VERSION 5.7 ;
  NOWIREEXTENSIONATPIN ON ;
  DIVIDERCHAR "/" ;
  BUSBITCHARS "[]" ;
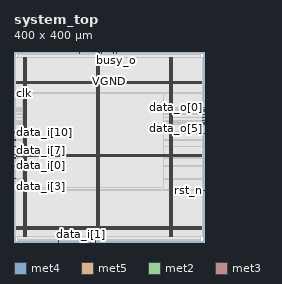
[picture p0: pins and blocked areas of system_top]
MACRO system_top
  CLASS BLOCK ;
  FOREIGN system_top ;
  ORIGIN 0.000 0.000 ;
  SIZE 400.000 BY 400.000 ;
  PIN VGND
    DIRECTION INOUT ;
    USE GROUND ;
    PORT
      LAYER met4 ;
        RECT 24.340 10.640 25.940 389.200 ;
    END
    PORT
      LAYER met4 ;
        RECT 177.940 10.640 179.540 389.200 ;
    END
    PORT
      LAYER met4 ;
        RECT 331.540 10.640 333.140 389.200 ;
    END
    PORT
      LAYER met5 ;
        RECT 5.280 30.030 394.460 31.630 ;
    END
    PORT
      LAYER met5 ;
        RECT 5.280 183.210 394.460 184.810 ;
    END
    PORT
      LAYER met5 ;
        RECT 5.280 336.390 394.460 337.990 ;
    END
  END VGND
  PIN VPWR
    DIRECTION INOUT ;
    USE POWER ;
    PORT
      LAYER met4 ;
        RECT 21.040 10.640 22.640 389.200 ;
    END
    PORT
      LAYER met4 ;
        RECT 174.640 10.640 176.240 389.200 ;
    END
    PORT
      LAYER met4 ;
        RECT 328.240 10.640 329.840 389.200 ;
    END
    PORT
      LAYER met5 ;
        RECT 5.280 26.730 394.460 28.330 ;
    END
    PORT
      LAYER met5 ;
        RECT 5.280 179.910 394.460 181.510 ;
    END
    PORT
      LAYER met5 ;
        RECT 5.280 333.090 394.460 334.690 ;
    END
  END VPWR
  PIN busy_o
    DIRECTION OUTPUT ;
    USE SIGNAL ;
    ANTENNADIFFAREA 0.340600 ;
    PORT
      LAYER met2 ;
        RECT 215.830 396.000 216.110 400.000 ;
    END
  END busy_o
  PIN clk
    DIRECTION INPUT ;
    USE SIGNAL ;
    ANTENNAGATEAREA 0.852000 ;
    ANTENNADIFFAREA 0.434700 ;
    PORT
      LAYER met3 ;
        RECT 0.000 312.840 4.000 313.440 ;
    END
  END clk
  PIN data_i[0]
    DIRECTION INPUT ;
    USE SIGNAL ;
    ANTENNAGATEAREA 0.213000 ;
    ANTENNADIFFAREA 0.434700 ;
    PORT
      LAYER met3 ;
        RECT 0.000 159.840 4.000 160.440 ;
    END
  END data_i[0]
  PIN data_i[10]
    DIRECTION INPUT ;
    USE SIGNAL ;
    ANTENNAGATEAREA 0.159000 ;
    ANTENNADIFFAREA 0.434700 ;
    PORT
      LAYER met3 ;
        RECT 0.000 231.240 4.000 231.840 ;
    END
  END data_i[10]
  PIN data_i[11]
    DIRECTION INPUT ;
    USE SIGNAL ;
    ANTENNAGATEAREA 0.159000 ;
    ANTENNADIFFAREA 0.434700 ;
    PORT
      LAYER met2 ;
        RECT 183.630 396.000 183.910 400.000 ;
    END
  END data_i[11]
  PIN data_i[12]
    DIRECTION INPUT ;
    USE SIGNAL ;
    ANTENNAGATEAREA 0.159000 ;
    ANTENNADIFFAREA 0.434700 ;
    PORT
      LAYER met3 ;
        RECT 0.000 227.840 4.000 228.440 ;
    END
  END data_i[12]
  PIN data_i[13]
    DIRECTION INPUT ;
    USE SIGNAL ;
    ANTENNAGATEAREA 0.159000 ;
    ANTENNADIFFAREA 0.434700 ;
    PORT
      LAYER met2 ;
        RECT 180.410 396.000 180.690 400.000 ;
    END
  END data_i[13]
  PIN data_i[14]
    DIRECTION INPUT ;
    USE SIGNAL ;
    ANTENNAGATEAREA 0.159000 ;
    ANTENNADIFFAREA 0.434700 ;
    PORT
      LAYER met2 ;
        RECT 177.190 396.000 177.470 400.000 ;
    END
  END data_i[14]
  PIN data_i[15]
    DIRECTION INPUT ;
    USE SIGNAL ;
    ANTENNAGATEAREA 0.213000 ;
    ANTENNADIFFAREA 0.434700 ;
    PORT
      LAYER met2 ;
        RECT 138.550 396.000 138.830 400.000 ;
    END
  END data_i[15]
  PIN data_i[1]
    DIRECTION INPUT ;
    USE SIGNAL ;
    ANTENNAGATEAREA 0.213000 ;
    ANTENNADIFFAREA 0.434700 ;
    PORT
      LAYER met2 ;
        RECT 141.770 0.000 142.050 4.000 ;
    END
  END data_i[1]
  PIN data_i[2]
    DIRECTION INPUT ;
    USE SIGNAL ;
    ANTENNAGATEAREA 0.159000 ;
    ANTENNADIFFAREA 0.434700 ;
    PORT
      LAYER met2 ;
        RECT 93.470 0.000 93.750 4.000 ;
    END
  END data_i[2]
  PIN data_i[3]
    DIRECTION INPUT ;
    USE SIGNAL ;
    ANTENNAGATEAREA 0.213000 ;
    ANTENNADIFFAREA 0.434700 ;
    PORT
      LAYER met3 ;
        RECT 0.000 132.640 4.000 133.240 ;
    END
  END data_i[3]
  PIN data_i[4]
    DIRECTION INPUT ;
    USE SIGNAL ;
    ANTENNAGATEAREA 0.159000 ;
    ANTENNADIFFAREA 0.434700 ;
    PORT
      LAYER met2 ;
        RECT 161.090 0.000 161.370 4.000 ;
    END
  END data_i[4]
  PIN data_i[5]
    DIRECTION INPUT ;
    USE SIGNAL ;
    ANTENNAGATEAREA 0.159000 ;
    ANTENNADIFFAREA 0.434700 ;
    PORT
      LAYER met2 ;
        RECT 170.750 0.000 171.030 4.000 ;
    END
  END data_i[5]
  PIN data_i[6]
    DIRECTION INPUT ;
    USE SIGNAL ;
    ANTENNAGATEAREA 0.159000 ;
    ANTENNADIFFAREA 0.434700 ;
    PORT
      LAYER met3 ;
        RECT 0.000 183.640 4.000 184.240 ;
    END
  END data_i[6]
  PIN data_i[7]
    DIRECTION INPUT ;
    USE SIGNAL ;
    ANTENNAGATEAREA 0.159000 ;
    ANTENNADIFFAREA 0.434700 ;
    PORT
      LAYER met3 ;
        RECT 0.000 176.840 4.000 177.440 ;
    END
  END data_i[7]
  PIN data_i[8]
    DIRECTION INPUT ;
    USE SIGNAL ;
    ANTENNAGATEAREA 0.213000 ;
    ANTENNADIFFAREA 0.434700 ;
    PORT
      LAYER met3 ;
        RECT 0.000 200.640 4.000 201.240 ;
    END
  END data_i[8]
  PIN data_i[9]
    DIRECTION INPUT ;
    USE SIGNAL ;
    ANTENNAGATEAREA 0.159000 ;
    ANTENNADIFFAREA 0.434700 ;
    PORT
      LAYER met3 ;
        RECT 0.000 214.240 4.000 214.840 ;
    END
  END data_i[9]
  PIN data_o[0]
    DIRECTION OUTPUT ;
    USE SIGNAL ;
    ANTENNADIFFAREA 0.340600 ;
    PORT
      LAYER met3 ;
        RECT 396.000 282.240 400.000 282.840 ;
    END
  END data_o[0]
  PIN data_o[1]
    DIRECTION OUTPUT ;
    USE SIGNAL ;
    ANTENNADIFFAREA 0.340600 ;
    PORT
      LAYER met3 ;
        RECT 396.000 278.840 400.000 279.440 ;
    END
  END data_o[1]
  PIN data_o[2]
    DIRECTION OUTPUT ;
    USE SIGNAL ;
    ANTENNADIFFAREA 0.340600 ;
    PORT
      LAYER met3 ;
        RECT 396.000 275.440 400.000 276.040 ;
    END
  END data_o[2]
  PIN data_o[3]
    DIRECTION OUTPUT ;
    USE SIGNAL ;
    ANTENNADIFFAREA 0.340600 ;
    PORT
      LAYER met3 ;
        RECT 396.000 268.640 400.000 269.240 ;
    END
  END data_o[3]
  PIN data_o[4]
    DIRECTION OUTPUT ;
    USE SIGNAL ;
    ANTENNADIFFAREA 0.340600 ;
    PORT
      LAYER met3 ;
        RECT 396.000 261.840 400.000 262.440 ;
    END
  END data_o[4]
  PIN data_o[5]
    DIRECTION OUTPUT ;
    USE SIGNAL ;
    ANTENNADIFFAREA 0.340600 ;
    PORT
      LAYER met3 ;
        RECT 396.000 255.040 400.000 255.640 ;
    END
  END data_o[5]
  PIN data_o[6]
    DIRECTION OUTPUT ;
    USE SIGNAL ;
    ANTENNADIFFAREA 0.340600 ;
    PORT
      LAYER met3 ;
        RECT 396.000 251.640 400.000 252.240 ;
    END
  END data_o[6]
  PIN data_o[7]
    DIRECTION OUTPUT ;
    USE SIGNAL ;
    ANTENNADIFFAREA 0.340600 ;
    PORT
      LAYER met3 ;
        RECT 396.000 248.240 400.000 248.840 ;
    END
  END data_o[7]
  PIN dvalid_i
    DIRECTION INPUT ;
    USE SIGNAL ;
    ANTENNAGATEAREA 0.196500 ;
    ANTENNADIFFAREA 0.434700 ;
    PORT
      LAYER met2 ;
        RECT 209.390 396.000 209.670 400.000 ;
    END
  END dvalid_i
  PIN rst_n
    DIRECTION INPUT ;
    USE SIGNAL ;
    ANTENNAGATEAREA 0.196500 ;
    ANTENNADIFFAREA 0.434700 ;
    PORT
      LAYER met3 ;
        RECT 396.000 108.840 400.000 109.440 ;
    END
  END rst_n
  PIN valid_o
    DIRECTION OUTPUT ;
    USE SIGNAL ;
    ANTENNADIFFAREA 0.340600 ;
    PORT
      LAYER met3 ;
        RECT 396.000 227.840 400.000 228.440 ;
    END
  END valid_o
  OBS
      LAYER nwell ;
        RECT 5.330 10.795 394.410 389.150 ;
      LAYER li1 ;
        RECT 5.520 10.795 394.220 389.045 ;
      LAYER met1 ;
        RECT 5.520 10.640 394.220 389.200 ;
      LAYER met2 ;
        RECT 6.530 395.720 138.270 396.000 ;
        RECT 139.110 395.720 176.910 396.000 ;
        RECT 177.750 395.720 180.130 396.000 ;
        RECT 180.970 395.720 183.350 396.000 ;
        RECT 184.190 395.720 209.110 396.000 ;
        RECT 209.950 395.720 215.550 396.000 ;
        RECT 216.390 395.720 392.750 396.000 ;
        RECT 6.530 4.280 392.750 395.720 ;
        RECT 6.530 4.000 93.190 4.280 ;
        RECT 94.030 4.000 141.490 4.280 ;
        RECT 142.330 4.000 160.810 4.280 ;
        RECT 161.650 4.000 170.470 4.280 ;
        RECT 171.310 4.000 392.750 4.280 ;
      LAYER met3 ;
        RECT 4.000 313.840 396.000 389.125 ;
        RECT 4.400 312.440 396.000 313.840 ;
        RECT 4.000 283.240 396.000 312.440 ;
        RECT 4.000 281.840 395.600 283.240 ;
        RECT 4.000 279.840 396.000 281.840 ;
        RECT 4.000 278.440 395.600 279.840 ;
        RECT 4.000 276.440 396.000 278.440 ;
        RECT 4.000 275.040 395.600 276.440 ;
        RECT 4.000 269.640 396.000 275.040 ;
        RECT 4.000 268.240 395.600 269.640 ;
        RECT 4.000 262.840 396.000 268.240 ;
        RECT 4.000 261.440 395.600 262.840 ;
        RECT 4.000 256.040 396.000 261.440 ;
        RECT 4.000 254.640 395.600 256.040 ;
        RECT 4.000 252.640 396.000 254.640 ;
        RECT 4.000 251.240 395.600 252.640 ;
        RECT 4.000 249.240 396.000 251.240 ;
        RECT 4.000 247.840 395.600 249.240 ;
        RECT 4.000 232.240 396.000 247.840 ;
        RECT 4.400 230.840 396.000 232.240 ;
        RECT 4.000 228.840 396.000 230.840 ;
        RECT 4.400 227.440 395.600 228.840 ;
        RECT 4.000 215.240 396.000 227.440 ;
        RECT 4.400 213.840 396.000 215.240 ;
        RECT 4.000 201.640 396.000 213.840 ;
        RECT 4.400 200.240 396.000 201.640 ;
        RECT 4.000 184.640 396.000 200.240 ;
        RECT 4.400 183.240 396.000 184.640 ;
        RECT 4.000 177.840 396.000 183.240 ;
        RECT 4.400 176.440 396.000 177.840 ;
        RECT 4.000 160.840 396.000 176.440 ;
        RECT 4.400 159.440 396.000 160.840 ;
        RECT 4.000 133.640 396.000 159.440 ;
        RECT 4.400 132.240 396.000 133.640 ;
        RECT 4.000 109.840 396.000 132.240 ;
        RECT 4.000 108.440 395.600 109.840 ;
        RECT 4.000 10.715 396.000 108.440 ;
      LAYER met4 ;
        RECT 16.855 113.735 20.640 313.305 ;
        RECT 23.040 113.735 23.940 313.305 ;
        RECT 26.340 113.735 174.240 313.305 ;
        RECT 176.640 113.735 177.540 313.305 ;
        RECT 179.940 113.735 315.265 313.305 ;
  END
END system_top
END LIBRARY

